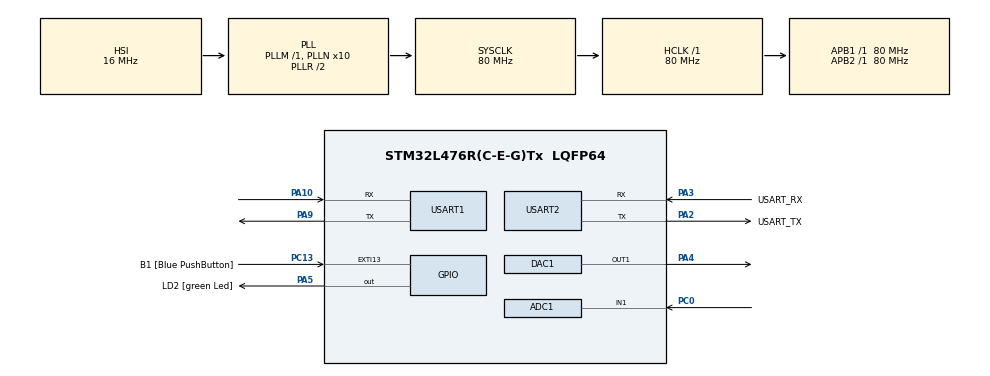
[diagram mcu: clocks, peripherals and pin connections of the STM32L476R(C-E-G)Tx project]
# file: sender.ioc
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ADC1.Channel-2\#ChannelRegularConversion=ADC_CHANNEL_1
ADC1.NbrOfConversionFlag=1
ADC1.OffsetNumber-2\#ChannelRegularConversion=ADC_OFFSET_NONE
ADC1.Rank-2\#ChannelRegularConversion=1
ADC1.SamplingTime-2\#ChannelRegularConversion=ADC_SAMPLETIME_2CYCLES_5
ADC1.master=1
Mcu.Family=STM32L4
Mcu.Name=STM32L476R(C-E-G)Tx
Mcu.Package=LQFP64
NVIC.PriorityGroup=NVIC_PRIORITYGROUP_4
PA10.Mode=Asynchronous
PA10.Signal=USART1_RX
PA13\ (JTMS-SWDIO).GPIO_Label=TMS
PA13\ (JTMS-SWDIO).Mode=Serial_Wire
PA13\ (JTMS-SWDIO).Signal=SYS_JTMS-SWDIO
PA14\ (JTCK-SWCLK).GPIO_Label=TCK
PA14\ (JTCK-SWCLK).Mode=Serial_Wire
PA14\ (JTCK-SWCLK).Signal=SYS_JTCK-SWCLK
PA2.GPIO_Label=USART_TX
PA2.GPIO_Mode=GPIO_MODE_AF_PP
PA2.GPIO_PuPd=GPIO_NOPULL
PA2.GPIO_Speed=GPIO_SPEED_FREQ_VERY_HIGH
PA2.Mode=Asynchronous
PA2.Signal=USART2_TX
PA3.GPIO_Label=USART_RX
PA3.GPIO_Mode=GPIO_MODE_AF_PP
PA3.GPIO_PuPd=GPIO_NOPULL
PA3.GPIO_Speed=GPIO_SPEED_FREQ_VERY_HIGH
PA3.Mode=Asynchronous
PA3.Signal=USART2_RX
PA4.Signal=COMP_DAC11_group
PA5.GPIO_Label=LD2 [green Led]
PA5.GPIO_ModeDefaultOutputPP=GPIO_MODE_OUTPUT_PP
PA5.GPIO_PuPd=GPIO_NOPULL
PA5.GPIO_Speed=GPIO_SPEED_FREQ_LOW
PA5.Signal=GPIO_Output
PA9.Mode=Asynchronous
PA9.Signal=USART1_TX
PB3\ (JTDO-TRACESWO).GPIO_Label=SWO
PB3\ (JTDO-TRACESWO).Signal=SYS_JTDO-SWO
PC0.Signal=ADCx_IN1
PC13.GPIO_Label=B1 [Blue PushButton]
PC13.GPIO_ModeDefaultEXTI=GPIO_MODE_IT_FALLING
PC13.GPIO_PuPd=GPIO_NOPULL
PC13.Signal=GPXTI13
PC14-OSC32_IN\ (PC14).Mode=LSE-External-Oscillator
PC14-OSC32_IN\ (PC14).Signal=RCC_OSC32_IN
PC15-OSC32_OUT\ (PC15).Mode=LSE-External-Oscillator
PC15-OSC32_OUT\ (PC15).Signal=RCC_OSC32_OUT
PH0-OSC_IN\ (PH0).Signal=RCC_OSC_IN
PH1-OSC_OUT\ (PH1).Signal=RCC_OSC_OUT
ProjectManager.HeapSize=0x200
ProjectManager.StackSize=0x400
ProjectManager.TargetToolchain=STM32CubeIDE
RCC.ADCFreq_Value=64000000
RCC.AHBFreq_Value=80000000
RCC.APB1Freq_Value=80000000
RCC.APB1TimFreq_Value=80000000
RCC.APB2Freq_Value=80000000
RCC.APB2TimFreq_Value=80000000
RCC.CortexFreq_Value=80000000
RCC.HCLKFreq_Value=80000000
RCC.HSE_VALUE=8000000
RCC.HSI_VALUE=16000000
RCC.MSI_VALUE=4000000
RCC.PLLN=10
RCC.PLLSourceVirtual=RCC_PLLSOURCE_HSI
RCC.PREFETCH_ENABLE=1
RCC.SYSCLKFreq_VALUE=80000000
RCC.SYSCLKSource=RCC_SYSCLKSOURCE_PLLCLK
RCC.USBFreq_Value=64000000
RCC.VCOOutputFreq_Value=160000000
SH.ADCx_IN1.0=ADC1_IN1,IN1-Single-Ended
SH.COMP_DAC11_group.0=DAC1_OUT1,DAC_OUT1
USART1.VirtualMode-Asynchronous=VM_ASYNC
USART2.VirtualMode-Asynchronous=VM_ASYNC
VP_TIM16_VS_ClockSourceINT.Mode=Enable_Timer
board=NUCLEO-L476RG

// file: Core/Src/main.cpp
/* USER CODE BEGIN Header */
/**
  ******************************************************************************
  * @file           : main.c
  * @brief          : Main program body
  ******************************************************************************
  * @attention
  *
  * <h2><center>&copy; Copyright (c) 2021 STMicroelectronics.
  * All rights reserved.</center></h2>
  *
  * This software component is licensed by ST under BSD 3-Clause license,
  * the "License"; You may not use this file except in compliance with the
  * License. You may obtain a copy of the License at:
  *                        opensource.org/licenses/BSD-3-Clause
  *
  ******************************************************************************
  */
/* USER CODE END Header */
#include <main.hpp>
#include <string.h>
#include <stdio.h>

/* USER CODE BEGIN PD */
#define SAMPLE_RATE 16000

/* USER CODE END PD */

ADC_HandleTypeDef hadc1;

DAC_HandleTypeDef hdac1;

UART_HandleTypeDef huart2;

TIM_HandleTypeDef htim16;

UART_HandleTypeDef huart1;

void SystemClock_Config(void);
static void MX_GPIO_Init(void);
static void MX_USART1_UART_Init(void);
static void MX_USART2_UART_Init(void);
static void MX_ADC1_Init(void);
static void MX_DAC1_Init(void);
static void MX_TIM16_Init(void);

int main(void)
{

  /* MCU Configuration--------------------------------------------------------*/

  /* Reset of all peripherals, Initializes the Flash interface and the Systick. */
  HAL_Init();

  /* Configure the system clock */
  SystemClock_Config();

  /* USER CODE BEGIN SysInit */
  MX_USART1_UART_Init();
  /* USER CODE END SysInit */

  /* Initialize all configured peripherals */
  MX_GPIO_Init();
  HAL_Delay(5000);
  MX_USART1_UART_Init();
  MX_USART2_UART_Init();
  MX_ADC1_Init();
  MX_DAC1_Init();
  MX_TIM16_Init();
  /* USER CODE BEGIN 2 */

  //start timer
  HAL_TIM_Base_Start(&htim16);
  HAL_GPIO_WritePin(LR_GPIO_Port, LR_Pin, GPIO_PIN_SET);
  /* USER CODE END 2 */

  ESP8266 ESP(&huart1);
  CommunicationAdaptor Adaptor(&ESP);
  Recorder REC(&htim16, &hadc1, &Adaptor);

  //startup
  while(ESP.Reset() == false)HAL_Delay(100);
  while(ESP.StartUp(1) == false)HAL_Delay(100);
  while(ESP.Connect(SSID, PASSWORD) == false)HAL_Delay(100);
  while(ESP.ConnectSocket(SOCKET_TYPE, SERVER_IP, SERVER_PORT) == false)HAL_Delay(100);

  REC.main();

  /* Infinite loop */
  while (1)
  {
  }
}

void SystemClock_Config(void)
{
  RCC_OscInitTypeDef RCC_OscInitStruct = {0};
  RCC_ClkInitTypeDef RCC_ClkInitStruct = {0};
  RCC_PeriphCLKInitTypeDef PeriphClkInit = {0};

  /** Initializes the RCC Oscillators according to the specified parameters
  * in the RCC_OscInitTypeDef structure.
  */
  RCC_OscInitStruct.OscillatorType = RCC_OSCILLATORTYPE_HSI;
  RCC_OscInitStruct.HSIState = RCC_HSI_ON;
  RCC_OscInitStruct.HSICalibrationValue = RCC_HSICALIBRATION_DEFAULT;
  RCC_OscInitStruct.PLL.PLLState = RCC_PLL_ON;
  RCC_OscInitStruct.PLL.PLLSource = RCC_PLLSOURCE_HSI;
  RCC_OscInitStruct.PLL.PLLM = 1;
  RCC_OscInitStruct.PLL.PLLN = 10;
  RCC_OscInitStruct.PLL.PLLP = RCC_PLLP_DIV7;
  RCC_OscInitStruct.PLL.PLLQ = RCC_PLLQ_DIV2;
  RCC_OscInitStruct.PLL.PLLR = RCC_PLLR_DIV2;
  if (HAL_RCC_OscConfig(&RCC_OscInitStruct) != HAL_OK)
  {
    Error_Handler();
  }
  /** Initializes the CPU, AHB and APB buses clocks
  */
  RCC_ClkInitStruct.ClockType = RCC_CLOCKTYPE_HCLK|RCC_CLOCKTYPE_SYSCLK
                              |RCC_CLOCKTYPE_PCLK1|RCC_CLOCKTYPE_PCLK2;
  RCC_ClkInitStruct.SYSCLKSource = RCC_SYSCLKSOURCE_PLLCLK;
  RCC_ClkInitStruct.AHBCLKDivider = RCC_SYSCLK_DIV1;
  RCC_ClkInitStruct.APB1CLKDivider = RCC_HCLK_DIV1;
  RCC_ClkInitStruct.APB2CLKDivider = RCC_HCLK_DIV1;

  if (HAL_RCC_ClockConfig(&RCC_ClkInitStruct, FLASH_LATENCY_4) != HAL_OK)
  {
    Error_Handler();
  }
  PeriphClkInit.PeriphClockSelection = RCC_PERIPHCLK_USART2|RCC_PERIPHCLK_ADC;
  PeriphClkInit.Usart2ClockSelection = RCC_USART2CLKSOURCE_PCLK1;
  PeriphClkInit.AdcClockSelection = RCC_ADCCLKSOURCE_PLLSAI1;
  PeriphClkInit.PLLSAI1.PLLSAI1Source = RCC_PLLSOURCE_HSI;
  PeriphClkInit.PLLSAI1.PLLSAI1M = 1;
  PeriphClkInit.PLLSAI1.PLLSAI1N = 8;
  PeriphClkInit.PLLSAI1.PLLSAI1P = RCC_PLLP_DIV7;
  PeriphClkInit.PLLSAI1.PLLSAI1Q = RCC_PLLQ_DIV2;
  PeriphClkInit.PLLSAI1.PLLSAI1R = RCC_PLLR_DIV2;
  PeriphClkInit.PLLSAI1.PLLSAI1ClockOut = RCC_PLLSAI1_ADC1CLK;
  if (HAL_RCCEx_PeriphCLKConfig(&PeriphClkInit) != HAL_OK)
  {
    Error_Handler();
  }
  /** Configure the main internal regulator output voltage
  */
  if (HAL_PWREx_ControlVoltageScaling(PWR_REGULATOR_VOLTAGE_SCALE1) != HAL_OK)
  {
    Error_Handler();
  }
}

static void MX_ADC1_Init(void)
{

  ADC_MultiModeTypeDef multimode = {0};
  ADC_ChannelConfTypeDef sConfig = {0};

  /** Common config
  */
  hadc1.Instance = ADC1;
  hadc1.Init.ClockPrescaler = ADC_CLOCK_ASYNC_DIV1;
  hadc1.Init.Resolution = ADC_RESOLUTION_8B; // 8 bit resolution
  hadc1.Init.DataAlign = ADC_DATAALIGN_RIGHT;
  hadc1.Init.ScanConvMode = ADC_SCAN_DISABLE;
  hadc1.Init.EOCSelection = ADC_EOC_SINGLE_CONV;
  hadc1.Init.LowPowerAutoWait = DISABLE;
  hadc1.Init.ContinuousConvMode = DISABLE;
  hadc1.Init.NbrOfConversion = 1;
  hadc1.Init.DiscontinuousConvMode = DISABLE;
  hadc1.Init.ExternalTrigConv = ADC_SOFTWARE_START;
  hadc1.Init.ExternalTrigConvEdge = ADC_EXTERNALTRIGCONVEDGE_NONE;
  hadc1.Init.DMAContinuousRequests = DISABLE;
  hadc1.Init.Overrun = ADC_OVR_DATA_PRESERVED;
  hadc1.Init.OversamplingMode = DISABLE;
  if (HAL_ADC_Init(&hadc1) != HAL_OK)
  {
    Error_Handler();
  }
  /** Configure the ADC multi-mode
  */
  multimode.Mode = ADC_MODE_INDEPENDENT;
  if (HAL_ADCEx_MultiModeConfigChannel(&hadc1, &multimode) != HAL_OK)
  {
    Error_Handler();
  }
  /** Configure Regular Channel
  */
  sConfig.Channel = ADC_CHANNEL_1;
  sConfig.Rank = ADC_REGULAR_RANK_1;
  sConfig.SamplingTime = ADC_SAMPLETIME_2CYCLES_5;
  sConfig.SingleDiff = ADC_SINGLE_ENDED;
  sConfig.OffsetNumber = ADC_OFFSET_NONE;
  sConfig.Offset = 0;
  if (HAL_ADC_ConfigChannel(&hadc1, &sConfig) != HAL_OK)
  {
    Error_Handler();
  }

}

static void MX_DAC1_Init(void)
{

  DAC_ChannelConfTypeDef sConfig = {0};

  /** DAC Initialization
  */
  hdac1.Instance = DAC1;
  if (HAL_DAC_Init(&hdac1) != HAL_OK)
  {
    Error_Handler();
  }
  /** DAC channel OUT1 config
  */
  sConfig.DAC_SampleAndHold = DAC_SAMPLEANDHOLD_DISABLE;
  sConfig.DAC_Trigger = DAC_TRIGGER_NONE;
  sConfig.DAC_OutputBuffer = DAC_OUTPUTBUFFER_ENABLE;
  sConfig.DAC_ConnectOnChipPeripheral = DAC_CHIPCONNECT_DISABLE;
  sConfig.DAC_UserTrimming = DAC_TRIMMING_FACTORY;
  if (HAL_DAC_ConfigChannel(&hdac1, &sConfig, DAC_CHANNEL_1) != HAL_OK)
  {
    Error_Handler();
  }

}

static void MX_USART1_UART_Init(void)
{

  huart1.Instance = USART1;
  huart1.Init.BaudRate = 460800;
  huart1.Init.WordLength = UART_WORDLENGTH_8B;
  huart1.Init.StopBits = UART_STOPBITS_1;
  huart1.Init.Parity = UART_PARITY_NONE;
  huart1.Init.Mode = UART_MODE_TX_RX;
  huart1.Init.HwFlowCtl = UART_HWCONTROL_NONE;
  huart1.Init.OverSampling = UART_OVERSAMPLING_16;
  huart1.Init.OneBitSampling = UART_ONE_BIT_SAMPLE_DISABLE;
  huart1.AdvancedInit.AdvFeatureInit = UART_ADVFEATURE_NO_INIT;
  if (HAL_UART_Init(&huart1) != HAL_OK)
  {
    Error_Handler();
  }

}

static void MX_USART2_UART_Init(void)
{

  huart2.Instance = USART2;
  huart2.Init.BaudRate = 115200;
  huart2.Init.WordLength = UART_WORDLENGTH_8B;
  huart2.Init.StopBits = UART_STOPBITS_1;
  huart2.Init.Parity = UART_PARITY_NONE;
  huart2.Init.Mode = UART_MODE_TX_RX;
  huart2.Init.HwFlowCtl = UART_HWCONTROL_NONE;
  huart2.Init.OverSampling = UART_OVERSAMPLING_16;
  huart2.Init.OneBitSampling = UART_ONE_BIT_SAMPLE_DISABLE;
  huart2.AdvancedInit.AdvFeatureInit = UART_ADVFEATURE_NO_INIT;
  if (HAL_UART_Init(&huart2) != HAL_OK)
  {
    Error_Handler();
  }

}

static void MX_GPIO_Init(void)
{
  GPIO_InitTypeDef GPIO_InitStruct = {0};

  /* GPIO Ports Clock Enable */
  __HAL_RCC_GPIOC_CLK_ENABLE();
  __HAL_RCC_GPIOH_CLK_ENABLE();
  __HAL_RCC_GPIOA_CLK_ENABLE();
  __HAL_RCC_GPIOB_CLK_ENABLE();

  /*Configure GPIO pin Output Level */
  HAL_GPIO_WritePin(LR_GPIO_Port, LR_Pin, GPIO_PIN_RESET);
  HAL_GPIO_WritePin(LG_GPIO_Port, LG_Pin, GPIO_PIN_RESET);
  HAL_GPIO_WritePin(LB_GPIO_Port, LB_Pin, GPIO_PIN_RESET);

  /*Configure GPIO pin : B1_Pin */
  GPIO_InitStruct.Pin = B1_Pin;
  GPIO_InitStruct.Mode = GPIO_MODE_IT_FALLING;
  GPIO_InitStruct.Pull = GPIO_NOPULL;
  HAL_GPIO_Init(B1_GPIO_Port, &GPIO_InitStruct);

  /*Configure GPIO pin : LR_Pin */
  GPIO_InitStruct.Pin = LR_Pin;
  GPIO_InitStruct.Mode = GPIO_MODE_OUTPUT_PP;
  GPIO_InitStruct.Pull = GPIO_NOPULL;
  GPIO_InitStruct.Speed = GPIO_SPEED_FREQ_LOW;
  HAL_GPIO_Init(LR_GPIO_Port, &GPIO_InitStruct);

  /*Configure GPIO pin : LG_Pin */
  GPIO_InitStruct.Pin = LG_Pin;
  GPIO_InitStruct.Mode = GPIO_MODE_OUTPUT_PP;
  GPIO_InitStruct.Pull = GPIO_NOPULL;
  GPIO_InitStruct.Speed = GPIO_SPEED_FREQ_LOW;
  HAL_GPIO_Init(LG_GPIO_Port, &GPIO_InitStruct);

  /*Configure GPIO pin : LB_Pin */
  GPIO_InitStruct.Pin = LB_Pin;
  GPIO_InitStruct.Mode = GPIO_MODE_OUTPUT_PP;
  GPIO_InitStruct.Pull = GPIO_NOPULL;
  GPIO_InitStruct.Speed = GPIO_SPEED_FREQ_LOW;
  HAL_GPIO_Init(LB_GPIO_Port, &GPIO_InitStruct);

}

static void MX_TIM16_Init(void)
{

  htim16.Instance = TIM16;
  htim16.Init.Prescaler = 500 -1;
  htim16.Init.CounterMode = TIM_COUNTERMODE_UP;
  htim16.Init.Period = 65535;
  htim16.Init.ClockDivision = TIM_CLOCKDIVISION_DIV1;
  htim16.Init.RepetitionCounter = 0;
  htim16.Init.AutoReloadPreload = TIM_AUTORELOAD_PRELOAD_DISABLE;
  if (HAL_TIM_Base_Init(&htim16) != HAL_OK)
  {
    Error_Handler();
  }

}

void Error_Handler(void)
{
  __disable_irq();
  while (1)
  {
  }
}

/************************ (C) COPYRIGHT STMicroelectronics *****END OF FILE****/
